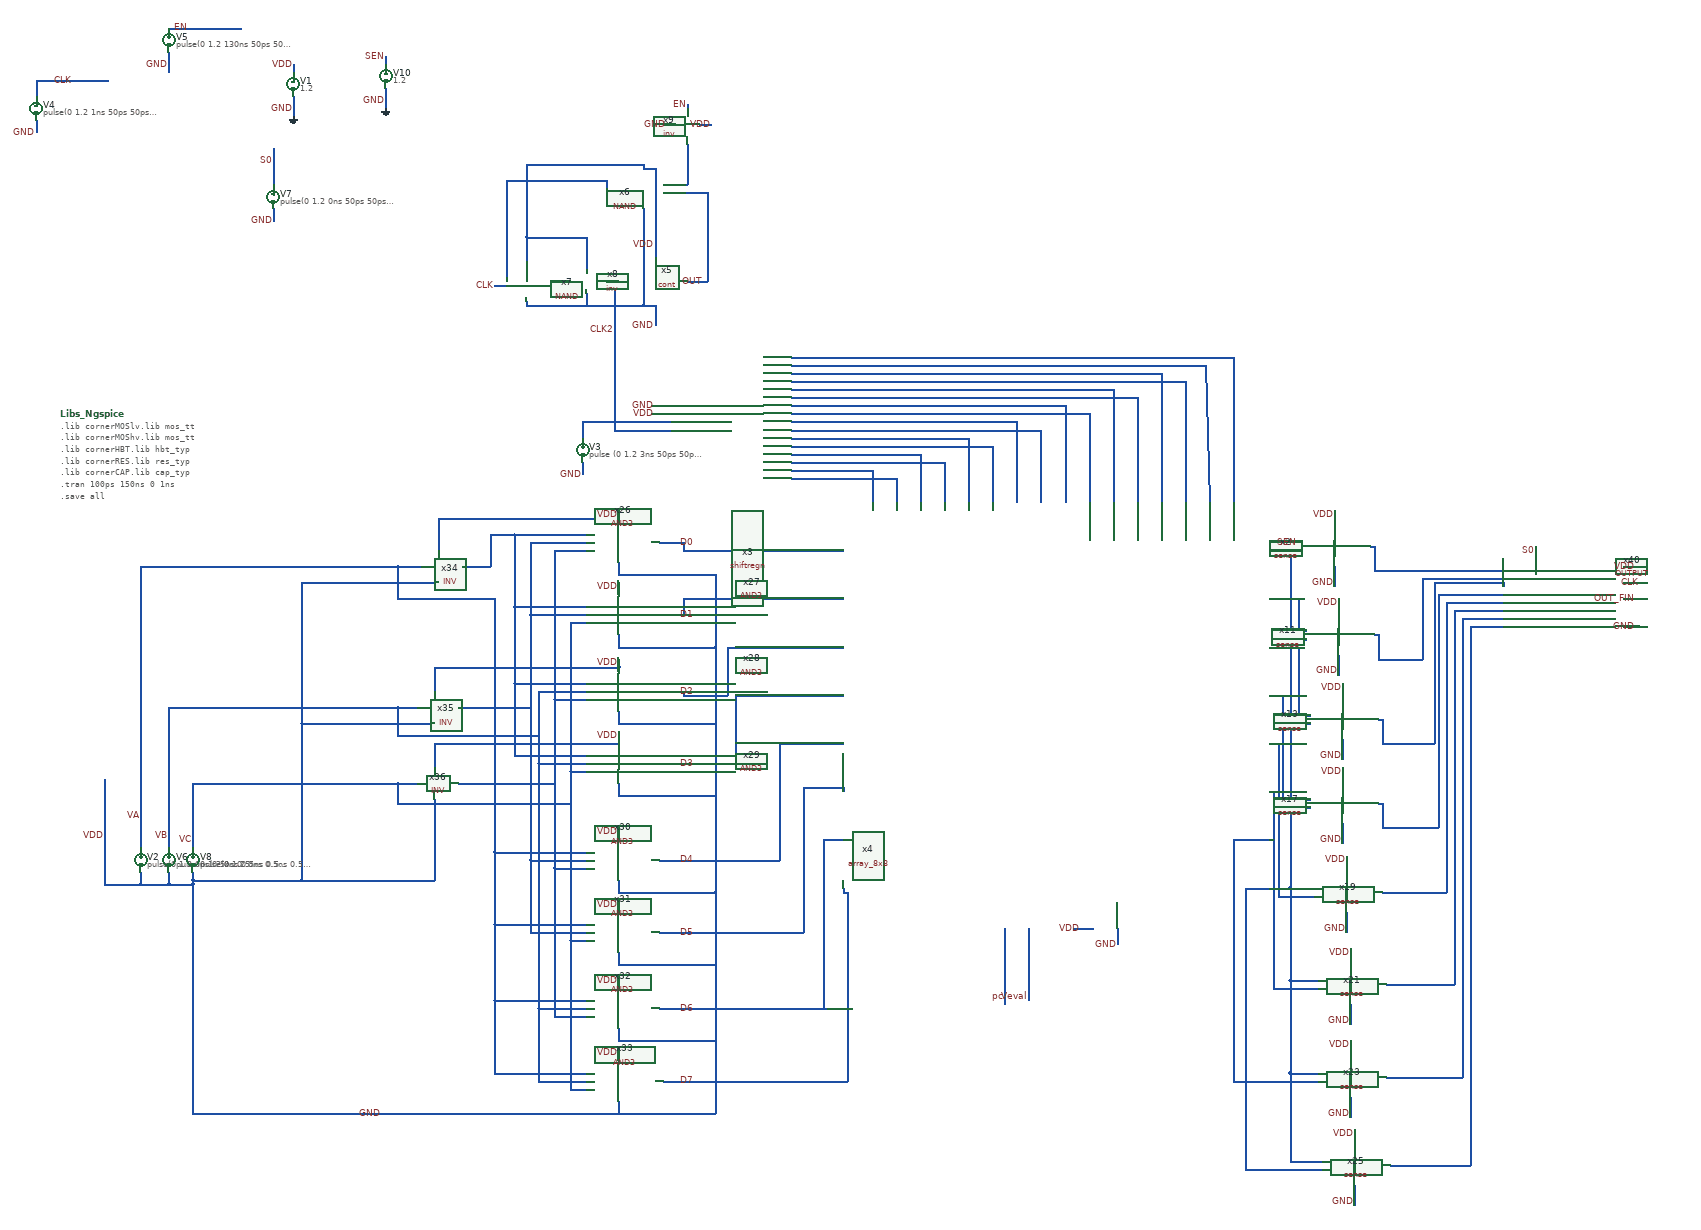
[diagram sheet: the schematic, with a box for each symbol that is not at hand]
v {xschem version=3.4.6 file_version=1.2}
G {}
K {}
V {}
S {}
E {}
N -360 960 -360 990 {lab=GND}
N -360 810 -360 900 {lab=S0}
N -950 740 -950 770 {lab=GND}
N -950 640 -950 680 {lab=CLK}
N -950 640 -770 640 {lab=CLK}
N -310 680 -310 730 {lab=GND}
N -310 600 -310 620 {lab=VDD}
N 2780 1800 2780 1820 {lab=S0}
N 3000 1850 3030 1850 {lab=VDD}
N 3000 1890 3040 1890 {lab=CLK}
N 3000 1930 3030 1930 {lab=OUT_FIN}
N 3000 2000 3040 2000 {lab=GND}
N 1630 2750 1680 2750 {lab=VDD}
N 1740 2750 1740 2790 {lab=GND}
N 930 1630 1190 1630 {lab=#net1}
N 1190 1630 1190 1690 {lab=#net1}
N 930 1610 1130 1610 {lab=#net2}
N 1130 1610 1130 1690 {lab=#net2}
N 930 1590 1310 1590 {lab=#net3}
N 1310 1590 1310 1690 {lab=#net3}
N 930 1570 1250 1570 {lab=#net4}
N 1250 1570 1250 1690 {lab=#net4}
N 930 1550 1430 1550 {lab=#net5}
N 1430 1550 1430 1690 {lab=#net5}
N 930 1530 1370 1530 {lab=#net6}
N 1370 1530 1370 1690 {lab=#net6}
N 930 1510 1550 1510 {lab=#net7}
N 1550 1510 1550 1690 {lab=#net7}
N 930 1490 1490 1490 {lab=#net8}
N 1490 1490 1490 1690 {lab=#net8}
N 930 1470 1670 1470 {lab=#net9}
N 1670 1470 1670 1690 {lab=#net9}
N 930 1450 1610 1450 {lab=#net10}
N 1610 1450 1610 1690 {lab=#net10}
N 930 1430 1790 1430 {lab=#net11}
N 1790 1430 1790 1690 {lab=#net11}
N 930 1410 1730 1410 {lab=#net12}
N 1730 1410 1730 1690 {lab=#net12}
N 930 1390 1910 1390 {lab=#net13}
N 1910 1390 1910 1690 {lab=#net13}
N 930 1370 1850 1370 {lab=#net14}
N 1850 1370 1850 1690 {lab=#net14}
N 930 1330 2030 1330 {lab=#net15}
N 2030 1330 2030 1690 {lab=#net15}
N 930 1350 1960 1350 {lab=#net16}
N 1960 1350 1970 1690 {lab=#net16}
N 590 1200 590 1250 {lab=GND}
N 670 1140 720 1140 {lab=OUT}
N 590 860 590 1080 {lab=VDD}
N 560 860 590 860 {lab=VDD}
N 560 960 560 1200 {lab=GND}
N 560 1200 590 1200 {lab=GND}
N 720 920 720 1140 {lab=OUT}
N 610 920 720 920 {lab=OUT}
N 610 900 670 900 {lab=#net17}
N 670 800 670 900 {lab=#net17}
N 580 1450 630 1450 {lab=GND}
N 580 1470 630 1470 {lab=VDD}
N 410 1490 630 1490 {lab=#net18}
N 410 1490 410 1530 {lab=#net18}
N 410 1590 410 1620 {lab=GND}
N 360 1140 380 1140 {lab=#net19}
N 490 1140 500 1140 {lab=CLK2}
N 220 890 220 1130 {lab=#net20}
N 220 890 470 890 {lab=#net20}
N 470 890 470 910 {lab=#net20}
N 190 1150 220 1150 {lab=CLK}
N 490 1140 490 1510 {lab=CLK2}
N 470 1140 490 1140 {lab=CLK2}
N 490 1510 630 1510 {lab=CLK2}
N 420 1200 560 1200 {lab=GND}
N 270 1190 270 1200 {lab=GND}
N 270 1030 270 1090 {lab=VDD}
N 270 850 560 850 {lab=VDD}
N 560 850 560 860 {lab=VDD}
N 420 1030 420 1110 {lab=VDD}
N 270 1030 420 1030 {lab=VDD}
N 270 850 270 1030 {lab=VDD}
N 420 1170 420 1200 {lab=GND}
N 270 1200 420 1200 {lab=GND}
N 670 700 670 710 {lab=EN}
N 610 750 640 750 {lab=GND}
N 700 750 730 750 {lab=VDD}
N 2120 1810 2200 1810 {lab=#net21}
N 2280 1710 2280 1750 {lab=VDD}
N 2280 1850 2280 1900 {lab=GND}
N 2380 1860 2700 1860 {lab=#net22}
N 2380 1800 2380 1860 {lab=#net22}
N 2370 1800 2380 1800 {lab=#net22}
N 2290 1930 2290 1970 {lab=VDD}
N 2290 2070 2290 2120 {lab=GND}
N 2390 2020 2390 2080 {lab=#net23}
N 2380 2020 2390 2020 {lab=#net23}
N 2300 2140 2300 2180 {lab=VDD}
N 2300 2280 2300 2330 {lab=GND}
N 2400 2230 2400 2290 {lab=#net24}
N 2390 2230 2400 2230 {lab=#net24}
N 2300 2350 2300 2390 {lab=VDD}
N 2300 2490 2300 2540 {lab=GND}
N 2400 2440 2400 2500 {lab=#net25}
N 2390 2440 2400 2440 {lab=#net25}
N 2310 2570 2310 2610 {lab=VDD}
N 2310 2710 2310 2760 {lab=GND}
N 2400 2660 2560 2660 {lab=#net26}
N 2320 2800 2320 2840 {lab=VDD}
N 2320 2940 2320 2990 {lab=GND}
N 2410 2890 2580 2890 {lab=#net27}
N 2320 3030 2320 3070 {lab=VDD}
N 2320 3170 2320 3220 {lab=GND}
N 2410 3120 2600 3120 {lab=#net28}
N 2330 3250 2330 3290 {lab=VDD}
N 2330 3390 2330 3440 {lab=GND}
N 2420 3340 2620 3340 {lab=#net29}
N 2170 1790 2200 1790 {lab=SEN}
N 2170 2010 2210 2010 {lab=SEN}
N 2170 2220 2220 2220 {lab=SEN}
N 2170 2010 2170 2220 {lab=SEN}
N 2170 1790 2170 2010 {lab=SEN}
N 2170 2220 2170 2430 {lab=SEN}
N 2170 2430 2220 2430 {lab=SEN}
N 2170 2430 2170 2650 {lab=SEN}
N 2170 2650 2230 2650 {lab=SEN}
N 2170 2650 2170 2880 {lab=SEN}
N 2170 2880 2240 2880 {lab=SEN}
N 2170 2880 2170 3110 {lab=SEN}
N 2170 3110 2240 3110 {lab=SEN}
N -690 2640 -620 2640 {lab=VDD}
N -780 2640 -690 2640 {lab=VDD}
N -620 2640 -560 2640 {lab=VDD}
N 500 1730 500 1740 {lab=VDD}
N 500 1890 500 1920 {lab=VDD}
N 500 2020 500 2050 {lab=VDD}
N 500 1840 500 1870 {lab=VDD}
N 500 2100 500 2110 {lab=VDD}
N 500 2260 500 2290 {lab=VDD}
N 500 2390 500 2420 {lab=VDD}
N 500 2210 500 2240 {lab=VDD}
N 500 2500 500 2530 {lab=VDD}
N 500 2680 500 2710 {lab=VDD}
N 500 2810 500 2840 {lab=VDD}
N 500 2630 500 2660 {lab=VDD}
N 500 2870 500 2900 {lab=VDD}
N 500 3050 500 3080 {lab=VDD}
N 500 3180 500 3210 {lab=VDD}
N 500 3000 500 3030 {lab=VDD}
N 600 1790 660 1790 {lab=D0}
N 600 2160 660 2160 {lab=D2}
N 600 2340 790 2340 {lab=D3}
N 600 2580 900 2580 {lab=D4}
N 600 1970 660 1970 {lab=D1}
N 600 2760 960 2760 {lab=D5}
N 1010 2950 1020 2950 {lab=D6}
N -690 2610 -690 2640 {lab=VDD}
N -560 2630 -560 2640 {lab=VDD}
N -620 2610 -620 2640 {lab=VDD}
N -780 2380 -780 2640 {lab=VDD}
N -690 1850 -690 2550 {lab=VA}
N -50 1850 10 1850 {lab=VA}
N -620 2200 -620 2550 {lab=VB}
N -560 2390 -560 2550 {lab=VC}
N 180 1770 180 1850 {lab=#net30}
N 240 1770 420 1770 {lab=#net30}
N 180 1770 240 1770 {lab=#net30}
N 240 1770 240 1950 {lab=#net30}
N 240 1950 420 1950 {lab=#net30}
N 240 1950 240 2140 {lab=#net30}
N 240 2140 420 2140 {lab=#net30}
N 240 2140 240 2320 {lab=#net30}
N 240 2320 420 2320 {lab=#net30}
N -50 1850 -50 1930 {lab=VA}
N -690 1850 -50 1850 {lab=VA}
N -50 1930 190 1930 {lab=VA}
N 190 2560 420 2560 {lab=VA}
N 190 2560 190 2740 {lab=VA}
N 190 2740 420 2740 {lab=VA}
N 190 2740 190 2930 {lab=VA}
N 190 2930 420 2930 {lab=VA}
N 190 2930 190 3110 {lab=VA}
N 190 3110 420 3110 {lab=VA}
N 100 2200 280 2200 {lab=#net31}
N 280 1970 280 2200 {lab=#net31}
N 280 1790 420 1790 {lab=#net31}
N 280 1970 420 1970 {lab=#net31}
N 280 1790 280 1970 {lab=#net31}
N 280 2200 280 2580 {lab=#net31}
N 280 2580 420 2580 {lab=#net31}
N 280 2580 280 2760 {lab=#net31}
N 280 2760 420 2760 {lab=#net31}
N -50 2200 -50 2270 {lab=VB}
N -620 2200 -50 2200 {lab=VB}
N -50 2270 300 2270 {lab=VB}
N 300 2160 300 2270 {lab=VB}
N 300 2160 420 2160 {lab=VB}
N 300 2270 300 2340 {lab=VB}
N 300 2340 420 2340 {lab=VB}
N 300 2340 300 2950 {lab=VB}
N 300 2950 420 2950 {lab=VB}
N 300 2950 300 3130 {lab=VB}
N 300 3130 420 3130 {lab=VB}
N 100 2390 340 2390 {lab=#net32}
N 340 2180 340 2390 {lab=#net32}
N 340 1810 420 1810 {lab=#net32}
N 340 2180 420 2180 {lab=#net32}
N 340 1810 340 2180 {lab=#net32}
N 340 2390 340 2600 {lab=#net32}
N 340 2600 420 2600 {lab=#net32}
N 340 2600 340 2970 {lab=#net32}
N 340 2970 420 2970 {lab=#net32}
N 380 2360 380 2440 {lab=VC}
N 380 2360 420 2360 {lab=VC}
N 380 1990 380 2360 {lab=VC}
N 380 1990 420 1990 {lab=VC}
N 380 2440 380 2780 {lab=VC}
N 380 2780 420 2780 {lab=VC}
N 380 2780 380 3150 {lab=VC}
N 380 3150 420 3150 {lab=VC}
N 500 3030 740 3030 {lab=VDD}
N 740 3030 740 3210 {lab=VDD}
N 500 3210 740 3210 {lab=VDD}
N 740 2840 740 3030 {lab=VDD}
N 500 1870 740 1870 {lab=VDD}
N 500 2050 740 2050 {lab=VDD}
N 740 1870 740 2050 {lab=VDD}
N 500 2240 740 2240 {lab=VDD}
N 740 2050 740 2240 {lab=VDD}
N 500 2420 740 2420 {lab=VDD}
N 740 2240 740 2420 {lab=VDD}
N 500 2660 740 2660 {lab=VDD}
N 740 2420 740 2660 {lab=VDD}
N 500 2840 740 2840 {lab=VDD}
N 740 2660 740 2840 {lab=VDD}
N -560 3210 500 3210 {lab=VDD}
N -560 2640 -560 3210 {lab=VDD}
N 110 1850 180 1850 {lab=#net30}
N -50 2200 0 2200 {lab=VB}
N -50 2440 380 2440 {lab=VC}
N -50 2390 -50 2440 {lab=VC}
N -50 2390 0 2390 {lab=VC}
N -560 2390 -50 2390 {lab=VC}
N 190 1930 190 2560 {lab=VA}
N 40 2430 40 2630 {lab=VDD}
N -290 2630 40 2630 {lab=VDD}
N -560 2610 -560 2630 {lab=VDD}
N -290 2240 40 2240 {lab=VDD}
N -560 2630 -290 2630 {lab=VDD}
N -290 1890 50 1890 {lab=VDD}
N -290 2240 -290 2630 {lab=VDD}
N -290 1890 -290 2240 {lab=VDD}
N 50 1730 50 1810 {lab=VDD}
N 50 1730 500 1730 {lab=VDD}
N 500 1710 500 1730 {lab=VDD}
N 40 2100 40 2160 {lab=VDD}
N 40 2100 500 2100 {lab=VDD}
N 500 2080 500 2100 {lab=VDD}
N 40 2290 40 2350 {lab=VDD}
N 40 2290 500 2290 {lab=VDD}
N 660 1810 1060 1810 {lab=D0}
N 660 1790 660 1810 {lab=D0}
N 660 1930 1060 1930 {lab=D1}
N 660 1930 660 1970 {lab=D1}
N 660 2160 660 2170 {lab=D2}
N 770 2050 1060 2050 {lab=D2}
N 770 2050 770 2170 {lab=D2}
N 660 2170 770 2170 {lab=D2}
N 790 2170 1060 2170 {lab=D3}
N 790 2170 790 2340 {lab=D3}
N 900 2290 900 2580 {lab=D4}
N 900 2290 1060 2290 {lab=D4}
N 960 2400 960 2760 {lab=D5}
N 960 2400 1060 2400 {lab=D5}
N 1010 2530 1060 2530 {lab=D6}
N 610 3130 1070 3130 {lab=D7}
N 1070 2660 1070 3130 {lab=D7}
N 1060 2660 1070 2660 {lab=D7}
N 1060 2650 1060 2660 {lab=D7}
N 1060 2400 1060 2410 {lab=D5}
N 1010 2530 1010 2950 {lab=D6}
N 600 2950 1010 2950 {lab=D6}
N 1460 2750 1460 2940 {lab=pc}
N 1520 2750 1520 2930 {lab=Veval}
N 2500 1880 2700 1880 {lab=#net23}
N 2500 1880 2500 2080 {lab=#net23}
N 2390 2080 2500 2080 {lab=#net23}
N 2400 2290 2530 2290 {lab=#net24}
N 2530 1890 2530 2290 {lab=#net24}
N 2530 1890 2700 1890 {lab=#net24}
N 2700 1890 2700 1900 {lab=#net24}
N 2540 1920 2700 1920 {lab=#net25}
N 2540 1920 2540 2500 {lab=#net25}
N 2400 2500 2540 2500 {lab=#net25}
N 2560 1940 2700 1940 {lab=#net26}
N 2560 1940 2560 2660 {lab=#net26}
N 2580 1960 2700 1960 {lab=#net27}
N 2580 1960 2580 2890 {lab=#net27}
N 2600 1980 2700 1980 {lab=#net28}
N 2600 1980 2600 3120 {lab=#net28}
N 2620 2000 2700 2000 {lab=#net29}
N 2620 2000 2620 3340 {lab=#net29}
N 2120 1930 2190 1930 {lab=#net33}
N 2190 1930 2190 2030 {lab=#net33}
N 2190 2030 2210 2030 {lab=#net33}
N 2120 2050 2190 2050 {lab=#net34}
N 2190 2050 2190 2240 {lab=#net34}
N 2190 2240 2220 2240 {lab=#net34}
N 2120 2170 2150 2170 {lab=#net35}
N 2150 2170 2150 2450 {lab=#net35}
N 2150 2450 2220 2450 {lab=#net35}
N 2120 2290 2140 2290 {lab=#net36}
N 2140 2290 2140 2670 {lab=#net36}
N 2140 2670 2230 2670 {lab=#net36}
N 2120 2410 2130 2410 {lab=#net37}
N 2130 2410 2130 2900 {lab=#net37}
N 2130 2900 2240 2900 {lab=#net37}
N 2030 2530 2120 2530 {lab=#net38}
N 2030 2530 2030 3130 {lab=#net38}
N 2030 3130 2240 3130 {lab=#net38}
N 2060 2650 2120 2650 {lab=#net39}
N 2060 2650 2060 3350 {lab=#net39}
N 2060 3350 2250 3350 {lab=#net39}
N 2170 3110 2170 3330 {lab=SEN}
N 2170 3330 2250 3330 {lab=SEN}
N -620 510 -440 510 {lab=EN}
N -620 570 -620 620 {lab=GND}
N -80 660 -80 710 {lab=GND}
N -80 580 -80 600 {lab=SEN}
C {simulator_commands_shown.sym} -890 1470 0 0 {
name=Libs_Ngspice
simulator=ngspice
only_toplevel=false
value="
.lib cornerMOSlv.lib mos_tt
.lib cornerMOShv.lib mos_tt
.lib cornerHBT.lib hbt_typ
.lib cornerRES.lib res_typ
.lib cornerCAP.lib cap_typ
.tran 100ps 150ns 0 1ns
.save all

"
      }
C {lab_wire.sym} -360 990 0 0 {name=p102 sig_type=std_logic lab=GND
}
C {vsource.sym} -360 930 0 0 {name=V7 value="pulse(0 1.2 0ns 50ps 50ps 12ns 1000ns)"}
C {lab_wire.sym} -360 840 0 0 {name=p103 sig_type=std_logic lab=S0
}
C {lab_wire.sym} -950 770 0 0 {name=p20 sig_type=std_logic lab=GND
}
C {vsource.sym} -950 710 0 0 {name=V4 value="pulse(0 1.2 1ns 50ps 50ps 5ns 10ns)"}
C {lab_wire.sym} -860 640 0 0 {name=p15 sig_type=std_logic lab=CLK



}
C {vsource.sym} -310 650 0 0 {name=V1 value=1.2 }
C {gnd.sym} -310 730 0 0 {name=l1 lab=GND
}
C {lab_wire.sym} -310 710 0 0 {name=p1 sig_type=std_logic lab=GND
}
C {lab_wire.sym} -310 600 0 0 {name=p2 sig_type=std_logic lab=VDD

}
C {/home/designer/shared/shiftregn.sym} 780 1500 0 0 {name=x3}
C {/home/designer/shared/OUTPUT.sym} 2850 1930 0 0 {name=x40}
C {lab_wire.sym} 3030 1850 0 0 {name=p25 sig_type=std_logic lab=VDD

}
C {lab_wire.sym} 3040 1890 0 0 {name=p35 sig_type=std_logic lab=CLK



}
C {lab_wire.sym} 3030 2000 0 0 {name=p38 sig_type=std_logic lab=GND

}
C {lab_wire.sym} 2780 1810 0 0 {name=p43 sig_type=std_logic lab=S0

}
C {/home/designer/shared/array_8x8.sym} 720 2920 0 0 {name=x4}
C {lab_wire.sym} 1740 2790 0 0 {name=p10 sig_type=std_logic lab=GND
}
C {lab_wire.sym} 1650 2750 0 0 {name=p12 sig_type=std_logic lab=VDD

}
C {/home/designer/shared/cont.sym} 650 1140 0 0 {name=x5}
C {lab_wire.sym} 590 1050 0 0 {name=p9 sig_type=std_logic lab=VDD

}
C {lab_wire.sym} 590 1250 0 0 {name=p11 sig_type=std_logic lab=GND
}
C {lab_wire.sym} 710 1140 0 0 {name=p13 sig_type=std_logic lab=OUT



}
C {/home/designer/shared/NAND.sym} 490 1000 0 1 {name=x6}
C {lab_wire.sym} 590 1450 0 0 {name=p14 sig_type=std_logic lab=GND
}
C {lab_wire.sym} 590 1470 0 0 {name=p16 sig_type=std_logic lab=VDD

}
C {vsource.sym} 410 1560 0 0 {name=V3 value="pulse (0 1.2 3ns 50ps 50ps 40ns 80ns)"}
C {lab_wire.sym} 410 1620 0 0 {name=p17 sig_type=std_logic lab=GND
}
C {/home/designer/shared/NAND.sym} 340 1230 0 0 {name=x7}
C {/home/designer/shared/inv.sym} 460 1230 0 0 {name=x8}
C {lab_wire.sym} 190 1150 2 1 {name=p18 sig_type=std_logic lab=CLK



}
C {lab_wire.sym} 670 700 0 0 {name=p19 sig_type=std_logic lab=EN

}
C {/home/designer/shared/inv.sym} 580 790 1 0 {name=x9}
C {lab_wire.sym} 730 750 0 0 {name=p21 sig_type=std_logic lab=VDD

}
C {lab_wire.sym} 620 750 0 0 {name=p22 sig_type=std_logic lab=GND
}
C {lab_wire.sym} 490 1260 2 1 {name=p23 sig_type=std_logic lab=CLK2



}
C {lab_wire.sym} 3030 1930 0 0 {name=p5 sig_type=std_logic lab=OUT_FIN

}
C {/home/designer/shared/sense.sym} 2350 1800 0 0 {name=x2}
C {lab_wire.sym} 2280 1890 0 0 {name=p6 sig_type=std_logic lab=GND
}
C {lab_wire.sym} 2280 1720 0 0 {name=p7 sig_type=std_logic lab=VDD

}
C {/home/designer/shared/sense.sym} 2360 2020 0 0 {name=x11}
C {lab_wire.sym} 2290 2110 0 0 {name=p26 sig_type=std_logic lab=GND
}
C {lab_wire.sym} 2290 1940 0 0 {name=p27 sig_type=std_logic lab=VDD

}
C {/home/designer/shared/sense.sym} 2370 2230 0 0 {name=x13}
C {lab_wire.sym} 2300 2320 0 0 {name=p31 sig_type=std_logic lab=GND
}
C {lab_wire.sym} 2300 2150 0 0 {name=p34 sig_type=std_logic lab=VDD

}
C {/home/designer/shared/sense.sym} 2370 2440 0 0 {name=x17}
C {lab_wire.sym} 2300 2530 0 0 {name=p39 sig_type=std_logic lab=GND
}
C {lab_wire.sym} 2300 2360 0 0 {name=p40 sig_type=std_logic lab=VDD

}
C {/home/designer/shared/sense.sym} 2380 2660 0 0 {name=x19}
C {lab_wire.sym} 2310 2750 0 0 {name=p44 sig_type=std_logic lab=GND
}
C {lab_wire.sym} 2310 2580 0 0 {name=p45 sig_type=std_logic lab=VDD

}
C {/home/designer/shared/sense.sym} 2390 2890 0 0 {name=x21}
C {lab_wire.sym} 2320 2980 0 0 {name=p48 sig_type=std_logic lab=GND
}
C {lab_wire.sym} 2320 2810 0 0 {name=p49 sig_type=std_logic lab=VDD

}
C {/home/designer/shared/sense.sym} 2390 3120 0 0 {name=x23}
C {lab_wire.sym} 2320 3210 0 0 {name=p52 sig_type=std_logic lab=GND
}
C {lab_wire.sym} 2320 3040 0 0 {name=p53 sig_type=std_logic lab=VDD

}
C {/home/designer/shared/sense.sym} 2400 3340 0 0 {name=x25}
C {lab_wire.sym} 2330 3430 0 0 {name=p56 sig_type=std_logic lab=GND
}
C {lab_wire.sym} 2330 3260 0 0 {name=p57 sig_type=std_logic lab=VDD

}
C {vsource.sym} -690 2580 0 0 {name=V2 value="pulse(0 1.2 0ns 0.5ns 0.5ns 5ns 10ns)"}
C {vsource.sym} -620 2580 0 0 {name=V6 value="pulse(0 1.2 0ns 0.5ns 0.5ns 10ns 20ns)"}
C {vsource.sym} -560 2580 0 0 {name=V8 value="pulse(0 1.2 0ns 0.5ns 0.5ns 20ns 40ns)"}
C {lab_pin.sym} -780 2520 0 0 {name=p58 sig_type=std_logic lab=VDD}
C {lab_pin.sym} -620 2520 0 0 {name=p59 sig_type=std_logic lab=VB}
C {lab_pin.sym} -560 2530 0 0 {name=p60 sig_type=std_logic lab=VC}
C {/home/designer/shared/AND3.sym} 500 1790 0 0 {name=x26}
C {lab_wire.sym} 650 1790 0 1 {name=p61 sig_type=std_logic lab=D0}
C {lab_pin.sym} -690 2470 0 0 {name=p62 sig_type=std_logic lab=VA}
C {/home/designer/shared/AND3.sym} 500 1970 0 0 {name=x27}
C {lab_pin.sym} 500 1720 0 0 {name=p63 sig_type=std_logic lab=VDD}
C {lab_pin.sym} 500 1900 0 0 {name=p64 sig_type=std_logic lab=VDD}
C {/home/designer/shared/AND3.sym} 500 2160 0 0 {name=x28}
C {/home/designer/shared/AND3.sym} 500 2340 0 0 {name=x29}
C {lab_pin.sym} 500 2090 0 0 {name=p65 sig_type=std_logic lab=VDD}
C {lab_pin.sym} 500 2270 0 0 {name=p66 sig_type=std_logic lab=VDD}
C {/home/designer/shared/AND3.sym} 500 2580 0 0 {name=x30}
C {/home/designer/shared/AND3.sym} 500 2760 0 0 {name=x31}
C {lab_pin.sym} 500 2510 0 0 {name=p67 sig_type=std_logic lab=VDD}
C {lab_pin.sym} 500 2690 0 0 {name=p68 sig_type=std_logic lab=VDD}
C {/home/designer/shared/AND3.sym} 500 2950 0 0 {name=x32}
C {/home/designer/shared/AND3.sym} 500 3130 0 0 {name=x33}
C {lab_pin.sym} 500 2880 0 0 {name=p69 sig_type=std_logic lab=VDD}
C {lab_pin.sym} 500 3060 0 0 {name=p70 sig_type=std_logic lab=VDD}
C {lab_wire.sym} 650 2160 0 1 {name=p71 sig_type=std_logic lab=D2}
C {lab_wire.sym} 650 2340 0 1 {name=p72 sig_type=std_logic lab=D3}
C {lab_wire.sym} 650 2580 0 1 {name=p73 sig_type=std_logic lab=D4}
C {lab_wire.sym} 650 1970 0 1 {name=p74 sig_type=std_logic lab=D1}
C {lab_wire.sym} 650 2760 0 1 {name=p75 sig_type=std_logic lab=D5}
C {lab_wire.sym} 650 2950 0 1 {name=p76 sig_type=std_logic lab=D6}
C {lab_wire.sym} 650 3130 0 1 {name=p77 sig_type=std_logic lab=D7}
C {/home/designer/shared/INV.sym} 60 1850 0 0 {name=x34}
C {/home/designer/shared/INV.sym} 50 2200 0 0 {name=x35}
C {/home/designer/shared/INV.sym} 50 2390 0 0 {name=x36}
C {lab_wire.sym} 1460 2920 0 0 {name=p78 sig_type=std_logic lab=pc

}
C {lab_wire.sym} 1520 2920 0 0 {name=p79 sig_type=std_logic lab=Veval
}
C {vsource.sym} -620 540 0 0 {name=V5 value="pulse(0 1.2 130ns 50ps 50ps 10ns 110ns)"}
C {lab_wire.sym} -570 510 0 0 {name=p3 sig_type=std_logic lab=EN

}
C {lab_wire.sym} -620 600 0 0 {name=p4 sig_type=std_logic lab=GND
}
C {vsource.sym} -80 630 0 0 {name=V10 value=1.2 }
C {gnd.sym} -80 710 0 0 {name=l3 lab=GND
}
C {lab_wire.sym} -80 690 0 0 {name=p8 sig_type=std_logic lab=GND
}
C {lab_wire.sym} -80 580 0 0 {name=p24 sig_type=std_logic lab=SEN

}
C {lab_wire.sym} 2190 1790 0 0 {name=p28 sig_type=std_logic lab=SEN

}
C {lab_wire.sym} -90 3210 0 0 {name=p29 sig_type=std_logic lab=GND
}
